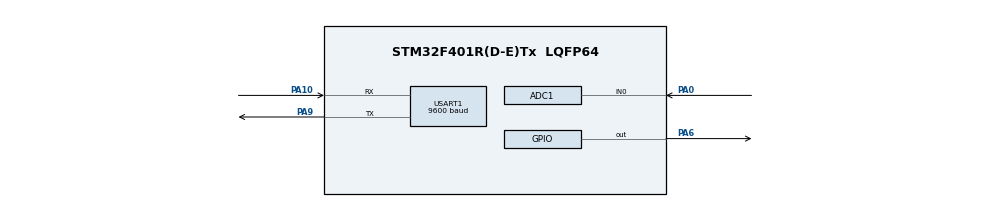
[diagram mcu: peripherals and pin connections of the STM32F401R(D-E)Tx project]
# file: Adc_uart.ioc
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ADC1.Channel-0\#ChannelRegularConversion=ADC_CHANNEL_0
ADC1.ClockPrescaler=ADC_CLOCK_SYNC_PCLK_DIV4
ADC1.ContinuousConvMode=ENABLE
ADC1.NbrOfConversionFlag=1
ADC1.Rank-0\#ChannelRegularConversion=1
ADC1.SamplingTime-0\#ChannelRegularConversion=ADC_SAMPLETIME_3CYCLES
ADC1.master=1
Mcu.Family=STM32F4
Mcu.Name=STM32F401R(D-E)Tx
Mcu.Package=LQFP64
NVIC.PriorityGroup=NVIC_PRIORITYGROUP_4
PA0-WKUP.Signal=ADCx_IN0
PA10.Mode=Asynchronous
PA10.Signal=USART1_RX
PA13.Mode=Serial_Wire
PA13.Signal=SYS_JTMS-SWDIO
PA14.Mode=Serial_Wire
PA14.Signal=SYS_JTCK-SWCLK
PA6.Signal=GPIO_Output
PA9.Mode=Asynchronous
PA9.Signal=USART1_TX
ProjectManager.HeapSize=0x200
ProjectManager.StackSize=0x400
ProjectManager.TargetToolchain=STM32CubeIDE
RCC.48MHZClocksFreq_Value=36000000
RCC.AHBFreq_Value=16000000
RCC.APB1CLKDivider=RCC_HCLK_DIV2
RCC.APB1Freq_Value=8000000
RCC.APB1TimFreq_Value=16000000
RCC.APB2Freq_Value=16000000
RCC.APB2TimFreq_Value=16000000
RCC.CortexFreq_Value=16000000
RCC.HCLKFreq_Value=16000000
RCC.HSE_VALUE=25000000
RCC.HSI_VALUE=16000000
RCC.LSE_VALUE=32768
RCC.PLLM=8
RCC.PLLN=72
RCC.SYSCLKFreq_VALUE=16000000
RCC.VCOOutputFreq_Value=144000000
SH.ADCx_IN0.0=ADC1_IN0,IN0
USART1.BaudRate=9600
USART1.VirtualMode=VM_ASYNC
VP_WWDG_VS_WWDG.Mode=WWDG_Activate
board=custom

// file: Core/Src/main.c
/* USER CODE BEGIN Header */
/**
  ******************************************************************************
  * @file           : main.c
  * @brief          : Main program body
  ******************************************************************************
  * @attention
  *
  * Copyright (c) 2023 STMicroelectronics.
  * All rights reserved.
  *
  * This software is licensed under terms that can be found in the LICENSE file
  * in the root directory of this software component.
  * If no LICENSE file comes with this software, it is provided AS-IS.
  *
  ******************************************************************************
  */
/* USER CODE END Header */
#include "main.h"

#include <stdio.h>
#include <string.h>

ADC_HandleTypeDef hadc1;

UART_HandleTypeDef huart1;

void SystemClock_Config(void);
static void MX_GPIO_Init(void);
static void MX_ADC1_Init(void);
static void MX_USART1_UART_Init(void);

/* USER CODE BEGIN 0 */

uint32_t adcvalue = 0;
float adcvoltage = 0.0;
char msg[25];

/* USER CODE END 0 */

int main(void)
{

  /* MCU Configuration--------------------------------------------------------*/

  /* Reset of all peripherals, Initializes the Flash interface and the Systick. */
  HAL_Init();

  /* Configure the system clock */
  SystemClock_Config();

  /* Initialize all configured peripherals */
  MX_GPIO_Init();
  MX_ADC1_Init();
  MX_USART1_UART_Init();

  /* Infinite loop */
  while (1)
  {
	  HAL_GPIO_TogglePin(GPIOA, GPIO_PIN_5);
	  HAL_Delay(300);

	  HAL_GPIO_TogglePin(GPIOA, GPIO_PIN_6);

	  HAL_ADC_Start(&hadc1);
	  HAL_ADC_PollForConversion(&hadc1, 10000);

	  adcvalue = HAL_ADC_GetValue(&hadc1);
	  adcvoltage = (adcvalue * 3.3) / 4096;

	  sprintf(msg, "Adc value = %ul \r\n", adcvoltage);
	  HAL_UART_Transmit(&huart1, (uint8_t*)msg, strlen(msg), 10000);
	  HAL_Delay(5000);
  }
}

void SystemClock_Config(void)
{
  RCC_OscInitTypeDef RCC_OscInitStruct = {0};
  RCC_ClkInitTypeDef RCC_ClkInitStruct = {0};

  /** Configure the main internal regulator output voltage
  */
  __HAL_RCC_PWR_CLK_ENABLE();
  __HAL_PWR_VOLTAGESCALING_CONFIG(PWR_REGULATOR_VOLTAGE_SCALE2);

  /** Initializes the RCC Oscillators according to the specified parameters
  * in the RCC_OscInitTypeDef structure.
  */
  RCC_OscInitStruct.OscillatorType = RCC_OSCILLATORTYPE_HSI;
  RCC_OscInitStruct.HSIState = RCC_HSI_ON;
  RCC_OscInitStruct.HSICalibrationValue = RCC_HSICALIBRATION_DEFAULT;
  RCC_OscInitStruct.PLL.PLLState = RCC_PLL_NONE;
  if (HAL_RCC_OscConfig(&RCC_OscInitStruct) != HAL_OK)
  {
    Error_Handler();
  }

  /** Initializes the CPU, AHB and APB buses clocks
  */
  RCC_ClkInitStruct.ClockType = RCC_CLOCKTYPE_HCLK|RCC_CLOCKTYPE_SYSCLK
                              |RCC_CLOCKTYPE_PCLK1|RCC_CLOCKTYPE_PCLK2;
  RCC_ClkInitStruct.SYSCLKSource = RCC_SYSCLKSOURCE_HSI;
  RCC_ClkInitStruct.AHBCLKDivider = RCC_SYSCLK_DIV1;
  RCC_ClkInitStruct.APB1CLKDivider = RCC_HCLK_DIV1;
  RCC_ClkInitStruct.APB2CLKDivider = RCC_HCLK_DIV1;

  if (HAL_RCC_ClockConfig(&RCC_ClkInitStruct, FLASH_LATENCY_0) != HAL_OK)
  {
    Error_Handler();
  }
}

static void MX_ADC1_Init(void)
{

  ADC_ChannelConfTypeDef sConfig = {0};

  /** Configure the global features of the ADC (Clock, Resolution, Data Alignment and number of conversion)
  */
  hadc1.Instance = ADC1;
  hadc1.Init.ClockPrescaler = ADC_CLOCK_SYNC_PCLK_DIV4;
  hadc1.Init.Resolution = ADC_RESOLUTION_12B;
  hadc1.Init.ScanConvMode = DISABLE;
  hadc1.Init.ContinuousConvMode = ENABLE;
  hadc1.Init.DiscontinuousConvMode = DISABLE;
  hadc1.Init.ExternalTrigConvEdge = ADC_EXTERNALTRIGCONVEDGE_NONE;
  hadc1.Init.ExternalTrigConv = ADC_SOFTWARE_START;
  hadc1.Init.DataAlign = ADC_DATAALIGN_RIGHT;
  hadc1.Init.NbrOfConversion = 1;
  hadc1.Init.DMAContinuousRequests = DISABLE;
  hadc1.Init.EOCSelection = ADC_EOC_SINGLE_CONV;
  if (HAL_ADC_Init(&hadc1) != HAL_OK)
  {
    Error_Handler();
  }

  /** Configure for the selected ADC regular channel its corresponding rank in the sequencer and its sample time.
  */
  sConfig.Channel = ADC_CHANNEL_0;
  sConfig.Rank = 1;
  sConfig.SamplingTime = ADC_SAMPLETIME_3CYCLES;
  if (HAL_ADC_ConfigChannel(&hadc1, &sConfig) != HAL_OK)
  {
    Error_Handler();
  }

}

static void MX_USART1_UART_Init(void)
{

  huart1.Instance = USART1;
  huart1.Init.BaudRate = 115200;
  huart1.Init.WordLength = UART_WORDLENGTH_8B;
  huart1.Init.StopBits = UART_STOPBITS_1;
  huart1.Init.Parity = UART_PARITY_NONE;
  huart1.Init.Mode = UART_MODE_TX_RX;
  huart1.Init.HwFlowCtl = UART_HWCONTROL_NONE;
  huart1.Init.OverSampling = UART_OVERSAMPLING_16;
  if (HAL_UART_Init(&huart1) != HAL_OK)
  {
    Error_Handler();
  }

}

static void MX_GPIO_Init(void)
{
  GPIO_InitTypeDef GPIO_InitStruct = {0};

  /* GPIO Ports Clock Enable */
  __HAL_RCC_GPIOA_CLK_ENABLE();

  /*Configure GPIO pin Output Level */
  HAL_GPIO_WritePin(GPIOA, GPIO_PIN_5|GPIO_PIN_6, GPIO_PIN_RESET);

  /*Configure GPIO pins : PA5 PA6 */
  GPIO_InitStruct.Pin = GPIO_PIN_5|GPIO_PIN_6;
  GPIO_InitStruct.Mode = GPIO_MODE_OUTPUT_PP;
  GPIO_InitStruct.Pull = GPIO_NOPULL;
  GPIO_InitStruct.Speed = GPIO_SPEED_FREQ_LOW;
  HAL_GPIO_Init(GPIOA, &GPIO_InitStruct);

}

void Error_Handler(void)
{
  __disable_irq();
  while (1)
  {
  }
}
